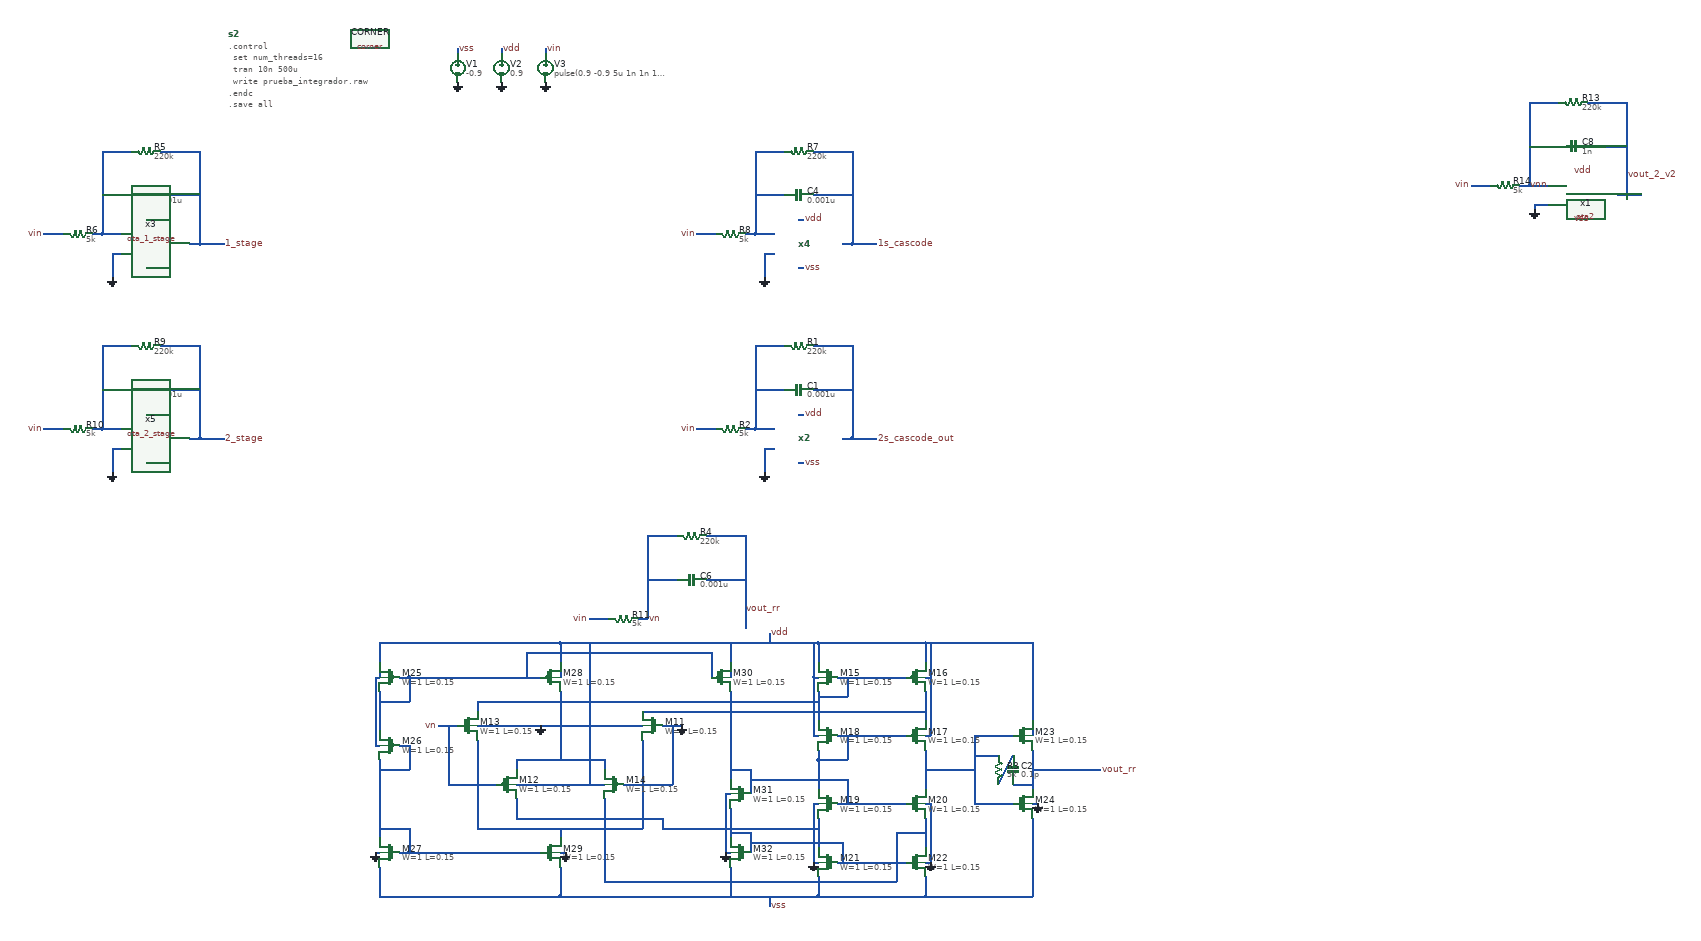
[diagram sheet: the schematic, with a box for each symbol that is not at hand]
v {xschem version=3.4.5 file_version=1.2
}
G {}
K {}
V {}
S {}
E {}
B 2 400 -320 1200 80 {flags=graph
y1=-1
y2=1.2
ypos1=0
ypos2=2
divy=5
subdivy=1
unity=1
x1=0.00019323799
x2=0.00039803799
divx=5
subdivx=1
xlabmag=1.0
ylabmag=1.0
node="vin
1_stage"
color="4 5"
dataset=-1
unitx=1
logx=0
logy=0
}
B 2 400 80 1200 480 {flags=graph
y1=-1
y2=1.3
ypos1=0
ypos2=2
divy=5
subdivy=1
unity=1
x1=0.00019323799
x2=0.00039803799
divx=5
subdivx=1
xlabmag=1.0
ylabmag=1.0
node="vin
2_stage"
color="4 5"
dataset=-1
unitx=1
logx=0
logy=0
}
B 2 1740 -320 2540 80 {flags=graph
y1=-1
y2=1
ypos1=0
ypos2=2
divy=5
subdivy=1
unity=1
x1=0.00019323799
x2=0.00039803799
divx=5
subdivx=1
xlabmag=1.0
ylabmag=1.0
node="vin
1s_cascode"
color="4 5"
dataset=-1
unitx=1
logx=0
logy=0
}
B 2 1740 80 2540 480 {flags=graph
y1=-0.9
y2=0.9
ypos1=0
ypos2=2
divy=5
subdivy=1
unity=1
x1=0.00019323799
x2=0.00039803799
divx=5
subdivx=1
xlabmag=1.0
ylabmag=1.0
node="vin
2s_cascode_out"
color="4 5"
dataset=-1
unitx=1
logx=0
logy=0
}
B 2 2100 540 2900 940 {flags=graph
y1=-1.1
y2=1.1
ypos1=0
ypos2=2
divy=5
subdivy=1
unity=1
x1=0.00019323799
x2=0.00039803799
divx=5
subdivx=1
xlabmag=1.0
ylabmag=1.0
node="vin
vout_rr"
color="4 5"
dataset=-1
unitx=1
logx=0
logy=0
}
B 2 1740 80 2540 480 {flags=graph
y1=-0.9
y2=0.9
ypos1=0
ypos2=2
divy=5
subdivy=1
unity=1
x1=0.00019323799
x2=0.00039803799
divx=5
subdivx=1
xlabmag=1.0
ylabmag=1.0
node="vin
2s_cascode_out"
color="4 5"
dataset=-1
unitx=1
logx=0
logy=0
}
B 2 1740 80 2540 480 {flags=graph
y1=-0.9
y2=0.9
ypos1=0
ypos2=2
divy=5
subdivy=1
unity=1
x1=0.00019323799
x2=0.00039803799
divx=5
subdivx=1
xlabmag=1.0
ylabmag=1.0
node="vin
2s_cascode_out"
color="4 5"
dataset=-1
unitx=1
logx=0
logy=0
}
B 2 3550 -190 4350 210 {flags=graph
y1=-0.9
y2=0.9
ypos1=0
ypos2=2
divy=5
subdivy=1
unity=1
x1=0.00019323799
x2=0.00039803799
divx=5
subdivx=1
xlabmag=1.0
ylabmag=1.0
node="vin
vout_2_v2"
color="4 5"
dataset=-1
unitx=1
logx=0
logy=0
}
N 860 -460 860 -450 {
lab=vdd}
N 770 -460 770 -450 {
lab=vss}
N 950 -460 950 -450 {
lab=vin}
N 130 -110 140 -110 {
lab=vdd}
N 130 -10 140 -10 {
lab=vss}
N 40 -190 40 -80 {
lab=#net1}
N 240 -190 240 -60 {
lab=1_stage}
N 220 -60 240 -60 {
lab=1_stage}
N 40 -250 40 -190 {
lab=#net1}
N 40 -250 100 -250 {
lab=#net1}
N 160 -250 240 -250 {
lab=1_stage}
N 240 -250 240 -190 {
lab=1_stage}
N 40 -160 100 -160 {
lab=#net1}
N 160 -160 240 -160 {
lab=1_stage}
N 20 -80 40 -80 {
lab=#net1}
N -80 -80 -40 -80 {
lab=vin}
N 240 -60 290 -60 {
lab=1_stage}
N 60 -80 80 -80 {
lab=#net1}
N 60 -40 60 10 {
lab=GND}
N 60 -40 80 -40 {
lab=GND}
N 40 -80 60 -80 {
lab=#net1}
N 130 290 140 290 {
lab=vdd}
N 130 390 140 390 {
lab=vss}
N 40 210 40 320 {
lab=#net2}
N 240 210 240 340 {
lab=2_stage}
N 220 340 240 340 {
lab=2_stage}
N 40 150 40 210 {
lab=#net2}
N 40 150 100 150 {
lab=#net2}
N 160 150 240 150 {
lab=2_stage}
N 240 150 240 210 {
lab=2_stage}
N 40 240 100 240 {
lab=#net2}
N 160 240 240 240 {
lab=2_stage}
N 20 320 40 320 {
lab=#net2}
N -80 320 -40 320 {
lab=vin}
N 240 340 290 340 {
lab=2_stage}
N 60 320 80 320 {
lab=#net2}
N 60 360 60 410 {
lab=GND}
N 60 360 80 360 {
lab=GND}
N 40 320 60 320 {
lab=#net2}
N 1470 -110 1480 -110 {
lab=vdd}
N 1470 -10 1480 -10 {
lab=vss}
N 1380 -190 1380 -80 {
lab=#net3}
N 1580 -190 1580 -60 {
lab=1s_cascode}
N 1560 -60 1580 -60 {
lab=1s_cascode}
N 1380 -250 1380 -190 {
lab=#net3}
N 1380 -250 1440 -250 {
lab=#net3}
N 1500 -250 1580 -250 {
lab=1s_cascode}
N 1580 -250 1580 -190 {
lab=1s_cascode}
N 1380 -160 1440 -160 {
lab=#net3}
N 1500 -160 1580 -160 {
lab=1s_cascode}
N 1360 -80 1380 -80 {
lab=#net3}
N 1260 -80 1300 -80 {
lab=vin}
N 1580 -60 1630 -60 {
lab=1s_cascode}
N 1400 -80 1420 -80 {
lab=#net3}
N 1400 -40 1400 10 {
lab=GND}
N 1400 -40 1420 -40 {
lab=GND}
N 1380 -80 1400 -80 {
lab=#net3}
N 1470 290 1480 290 {
lab=vdd}
N 1470 390 1480 390 {
lab=vss}
N 1380 210 1380 320 {
lab=#net4}
N 1580 210 1580 340 {
lab=2s_cascode_out}
N 1560 340 1580 340 {
lab=2s_cascode_out}
N 1380 150 1380 210 {
lab=#net4}
N 1380 150 1440 150 {
lab=#net4}
N 1500 150 1580 150 {
lab=2s_cascode_out}
N 1580 150 1580 210 {
lab=2s_cascode_out}
N 1380 240 1440 240 {
lab=#net4}
N 1500 240 1580 240 {
lab=2s_cascode_out}
N 1360 320 1380 320 {
lab=#net4}
N 1260 320 1300 320 {
lab=vin}
N 1580 340 1630 340 {
lab=2s_cascode_out}
N 1400 320 1420 320 {
lab=#net4}
N 1400 360 1400 410 {
lab=GND}
N 1400 360 1420 360 {
lab=GND}
N 1380 320 1400 320 {
lab=#net4}
N 890 1000 890 1020 {
lab=#net5}
N 890 1000 1070 1000 {
lab=#net5}
N 1070 1000 1070 1020 {
lab=#net5}
N 810 960 810 1140 {
lab=#net6}
N 1150 960 1150 1140 {
lab=#net6}
N 810 1140 1150 1140 {
lab=#net6}
N 730 930 770 930 {
lab=vn}
N 750 930 750 1050 {
lab=vn}
N 750 1050 850 1050 {
lab=vn}
N 1110 1050 1210 1050 {
lab=GND}
N 1210 930 1210 1050 {
lab=GND}
N 1190 930 1230 930 {
lab=GND}
N 980 860 980 1000 {
lab=#net5}
N 980 760 980 800 {
lab=vdd}
N 980 1140 980 1160 {
lab=#net6}
N 1510 860 1510 920 {
lab=#net7}
N 1730 860 1730 920 {
lab=#net8}
N 1550 830 1690 830 {
lab=#net7}
N 1510 760 1510 800 {
lab=vdd}
N 1510 760 1730 760 {
lab=vdd}
N 1730 760 1730 800 {
lab=vdd}
N 1510 1000 1550 1000 {
lab=#net9}
N 1510 980 1510 1000 {
lab=#net9}
N 1510 1120 1510 1180 {
lab=#net10}
N 1730 1120 1730 1180 {
lab=#net11}
N 1510 1000 1510 1060 {
lab=#net9}
N 1730 980 1730 1060 {
lab=#net12}
N 1510 1240 1510 1280 {
lab=vss}
N 1510 1280 1730 1280 {
lab=vss}
N 1730 1240 1730 1280 {
lab=vss}
N 1550 1090 1690 1090 {
lab=#net13}
N 1550 1210 1690 1210 {
lab=#net14}
N 1310 1280 1510 1280 {
lab=vss}
N 980 1220 980 1280 {
lab=vss}
N 980 1280 1310 1280 {
lab=vss}
N 1150 900 1730 900 {
lab=#net8}
N 810 880 810 900 {
lab=#net7}
N 810 880 1490 880 {
lab=#net7}
N 1490 880 1510 880 {
lab=#net7}
N 1510 870 1570 870 {
lab=#net7}
N 1570 830 1570 870 {
lab=#net7}
N 890 1080 890 1120 {
lab=#net10}
N 890 1120 1190 1120 {
lab=#net10}
N 1190 1140 1510 1140 {
lab=#net10}
N 1070 1080 1070 1250 {
lab=#net11}
N 1070 1250 1670 1250 {
lab=#net11}
N 1670 1160 1670 1250 {
lab=#net11}
N 980 760 1510 760 {
lab=vdd}
N 1410 740 1410 760 {
lab=vdd}
N 1410 1280 1410 1300 {
lab=vss}
N 1550 950 1690 950 {
lab=#net9}
N 1570 950 1570 1000 {
lab=#net9}
N 1550 1000 1570 1000 {
lab=#net9}
N 1830 950 1830 1090 {
lab=#net12}
N 1730 760 1950 760 {
lab=vdd}
N 1950 760 1950 920 {
lab=vdd}
N 1730 1280 1950 1280 {
lab=vss}
N 1950 1120 1950 1280 {
lab=vss}
N 1950 980 1950 1060 {
lab=vout_rr}
N 1950 1020 2090 1020 {
lab=vout_rr}
N 810 930 1150 930 {
lab=GND}
N 890 1050 1070 1050 {
lab=vdd}
N 1040 760 1040 1050 {
lab=vdd}
N 1500 830 1510 830 {
lab=vdd}
N 1500 760 1500 830 {
lab=vdd}
N 1500 830 1500 950 {
lab=vdd}
N 1500 950 1510 950 {
lab=vdd}
N 1730 950 1740 950 {
lab=vdd}
N 1740 760 1740 950 {
lab=vdd}
N 1730 830 1740 830 {
lab=vdd}
N 1500 1090 1510 1090 {
lab=GND}
N 1500 1210 1510 1210 {
lab=GND}
N 1730 1090 1740 1090 {
lab=GND}
N 1730 1210 1740 1210 {
lab=GND}
N 1560 1170 1560 1210 {
lab=#net14}
N 1670 1150 1730 1150 {
lab=#net11}
N 1670 1150 1670 1160 {
lab=#net11}
N 1950 920 1950 950 {
lab=vdd}
N 650 830 670 830 {
lab=#net15}
N 670 830 670 880 {
lab=#net15}
N 610 880 670 880 {
lab=#net15}
N 610 860 610 940 {
lab=#net15}
N 610 1000 610 1160 {
lab=#net16}
N 610 1020 670 1020 {
lab=#net16}
N 670 970 670 1020 {
lab=#net16}
N 650 970 670 970 {
lab=#net16}
N 610 1220 610 1280 {
lab=vss}
N 610 1140 670 1140 {
lab=#net16}
N 670 1140 670 1190 {
lab=#net16}
N 650 1190 670 1190 {
lab=#net16}
N 600 970 610 970 {
lab=vdd}
N 600 830 600 970 {
lab=vdd}
N 600 830 610 830 {
lab=vdd}
N 610 800 610 830 {
lab=vdd}
N 610 760 610 800 {
lab=vdd}
N 980 800 980 830 {
lab=vdd}
N 910 780 910 830 {
lab=#net15}
N 910 780 1290 780 {
lab=#net15}
N 1290 780 1290 830 {
lab=#net15}
N 1330 760 1330 800 {
lab=vdd}
N 1330 800 1330 830 {
lab=vdd}
N 1190 1120 1190 1140 {
lab=#net10}
N 1330 860 1330 1040 {
lab=#net13}
N 1330 1100 1330 1160 {
lab=#net14}
N 1330 1220 1330 1280 {
lab=vss}
N 1330 1150 1370 1150 {
lab=#net14}
N 1370 1150 1370 1190 {
lab=#net14}
N 1370 1170 1560 1170 {
lab=#net14}
N 1330 1020 1370 1020 {
lab=#net13}
N 1370 1020 1370 1070 {
lab=#net13}
N 1570 1040 1570 1090 {
lab=#net13}
N 1390 1040 1570 1040 {
lab=#net13}
N 1370 1040 1390 1040 {
lab=#net13}
N 1320 1070 1330 1070 {
lab=GND}
N 1320 1070 1320 1190 {
lab=GND}
N 1320 1190 1330 1190 {
lab=GND}
N 610 760 980 760 {
lab=vdd}
N 670 830 940 830 {
lab=#net15}
N 610 1280 980 1280 {
lab=vss}
N 670 1190 940 1190 {
lab=#net16}
N 1730 1020 1830 1020 {
lab=#net12}
N 1830 950 1910 950 {
lab=#net12}
N 1830 1090 1910 1090 {
lab=#net12}
N 1830 990 1880 990 {
lab=#net12}
N 1880 1050 1910 990 {
lab=#net17}
N 1910 1050 1950 1050 {
lab=vout_rr}
N 1160 600 1160 710 {
lab=vn}
N 1360 600 1360 730 {
lab=vout_rr}
N 1160 540 1160 600 {
lab=vn}
N 1160 540 1220 540 {
lab=vn}
N 1280 540 1360 540 {
lab=vout_rr}
N 1360 540 1360 600 {
lab=vout_rr}
N 1160 630 1220 630 {
lab=vn}
N 1280 630 1360 630 {
lab=vout_rr}
N 1040 710 1080 710 {
lab=vin}
N 1140 710 1160 710 {
lab=vn}
N 2970 -290 2970 -180 {
lab=vnn}
N 3170 -290 3170 -160 {
lab=vout_2_v2}
N 2970 -350 2970 -290 {
lab=vnn}
N 2970 -350 3030 -350 {
lab=vnn}
N 3090 -350 3170 -350 {
lab=vout_2_v2}
N 3170 -350 3170 -290 {
lab=vout_2_v2}
N 2970 -260 3030 -260 {
lab=vnn}
N 3090 -260 3170 -260 {
lab=vout_2_v2}
N 2850 -180 2890 -180 {
lab=vin}
N 2950 -180 2970 -180 {
lab=vnn}
N 600 1190 610 1190 {
lab=GND}
N 980 1190 990 1190 {
lab=GND}
N 1500 1090 1500 1210 {
lab=GND}
N 1740 1090 1740 1210 {
lab=GND}
N 1950 1090 1960 1090 {
lab=GND}
N 3150 -160 3200 -160 {
lab=vout_2_v2}
N 2970 -180 3010 -180 {
lab=vnn}
N 2980 -140 3010 -140 {
lab=GND}
N 2980 -140 2980 -130 {
lab=GND}
C {devices/vsource.sym} 770 -420 0 0 {name=V1 value=-0.9}
C {devices/gnd.sym} 770 -390 0 0 {name=l1 lab=GND}
C {devices/vsource.sym} 860 -420 0 0 {name=V2 value=0.9}
C {devices/gnd.sym} 860 -390 0 0 {name=l2 lab=GND}
C {devices/lab_wire.sym} 860 -460 0 1 {name=p1 sig_type=std_logic lab=vdd}
C {devices/lab_wire.sym} 770 -460 0 1 {name=p2 sig_type=std_logic lab=vss}
C {devices/vsource.sym} 950 -420 0 0 {name=V3 value="pulse(0.9 -0.9 5u 1n 1n 10u 20u)"}
C {devices/gnd.sym} 950 -390 0 0 {name=l3 lab=GND}
C {devices/lab_wire.sym} 950 -460 0 1 {name=p5 sig_type=std_logic lab=vin}
C {sky130_fd_pr/corner.sym} 590 -480 0 0 {name=CORNER only_toplevel=true corner=tt}
C {devices/launcher.sym} 1280 -430 0 0 {name=h5
descr="load waves" 
tclcommand="xschem raw_read $netlist_dir/prueba_integrador.raw tran"
}
C {devices/lab_wire.sym} 140 -110 0 1 {name=p12 sig_type=std_logic lab=vdd}
C {devices/lab_wire.sym} 140 -10 2 0 {name=p13 sig_type=std_logic lab=vss}
C {devices/res.sym} 130 -250 1 0 {name=R5
value=220k
footprint=1206
device=resistor
m=1}
C {devices/res.sym} -10 -80 1 0 {name=R6
value=5k
footprint=1206
device=resistor
m=1}
C {devices/capa.sym} 130 -160 3 0 {name=C3
m=1
value=0.001u
footprint=1206
device="ceramic capacitor"}
C {devices/lab_wire.sym} -80 -80 0 0 {name=p14 sig_type=std_logic lab=vin}
C {devices/gnd.sym} 60 10 0 0 {name=l6 lab=GND}
C {devices/lab_wire.sym} 290 -60 0 1 {name=p15 sig_type=std_logic lab=1_stage}
C {/home/user/Documentos/ota_1_stage.sym} 130 -60 0 0 {name=x3}
C {devices/lab_wire.sym} 140 290 0 1 {name=p17 sig_type=std_logic lab=vdd}
C {devices/lab_wire.sym} 140 390 2 0 {name=p20 sig_type=std_logic lab=vss}
C {devices/res.sym} 130 150 1 0 {name=R9
value=220k
footprint=1206
device=resistor
m=1}
C {devices/res.sym} -10 320 1 0 {name=R10
value=5k
footprint=1206
device=resistor
m=1}
C {devices/capa.sym} 130 240 3 0 {name=C5
m=1
value=0.001u
footprint=1206
device="ceramic capacitor"}
C {devices/lab_wire.sym} -80 320 0 0 {name=p21 sig_type=std_logic lab=vin}
C {devices/gnd.sym} 60 410 0 0 {name=l8 lab=GND}
C {devices/lab_wire.sym} 290 340 0 1 {name=p22 sig_type=std_logic lab=2_stage}
C {/home/user/Documentos/ota_2_stage.sym} 130 340 0 0 {name=x5}
C {devices/lab_wire.sym} 1480 -110 0 1 {name=p16 sig_type=std_logic lab=vdd}
C {devices/lab_wire.sym} 1480 -10 2 0 {name=p18 sig_type=std_logic lab=vss}
C {devices/res.sym} 1470 -250 1 0 {name=R7
value=220k
footprint=1206
device=resistor
m=1}
C {devices/res.sym} 1330 -80 1 0 {name=R8
value=5k
footprint=1206
device=resistor
m=1}
C {devices/capa.sym} 1470 -160 3 0 {name=C4
m=1
value=0.001u
footprint=1206
device="ceramic capacitor"}
C {devices/lab_wire.sym} 1260 -80 0 0 {name=p19 sig_type=std_logic lab=vin}
C {devices/gnd.sym} 1400 10 0 0 {name=l7 lab=GND}
C {devices/lab_wire.sym} 1630 -60 0 1 {name=p23 sig_type=std_logic lab=1s_cascode}
C {/home/user/Documentos/ota_1_stage_cascode.sym} 1470 -60 0 0 {name=x4}
C {devices/lab_wire.sym} 1480 290 0 1 {name=p3 sig_type=std_logic lab=vdd}
C {devices/lab_wire.sym} 1480 390 2 0 {name=p4 sig_type=std_logic lab=vss}
C {devices/res.sym} 1470 150 1 0 {name=R1
value=220k
footprint=1206
device=resistor
m=1}
C {devices/res.sym} 1330 320 1 0 {name=R2
value=5k
footprint=1206
device=resistor
m=1}
C {devices/capa.sym} 1470 240 3 0 {name=C1
m=1
value=0.001u
footprint=1206
device="ceramic capacitor"}
C {devices/lab_wire.sym} 1260 320 0 0 {name=p6 sig_type=std_logic lab=vin}
C {devices/gnd.sym} 1400 410 0 0 {name=l4 lab=GND}
C {devices/lab_wire.sym} 1630 340 0 1 {name=p7 sig_type=std_logic lab=2s_cascode_out}
C {devices/code_shown.sym} 300 -490 0 0 {name=s2 only_toplevel=false value="
.control
 set num_threads=16
 tran 10n 500u
 write prueba_integrador.raw
.endc
.save all" }
C {/home/user/Documentos/ota_2_stage_cascode_out.sym} 1470 340 0 0 {name=x2}
C {sky130_fd_pr/pfet_01v8.sym} 870 1050 0 0 {name=M12
L=0.15
W=1
nf=1 mult=1
model=pfet_01v8
spiceprefix=X
}
C {sky130_fd_pr/nfet_01v8.sym} 790 930 0 0 {name=M13
L=0.15
W=1  
nf=1 mult=1
model=nfet_01v8
spiceprefix=X
}
C {sky130_fd_pr/nfet_01v8.sym} 1170 930 0 1 {name=M11
L=0.15
W=1  
nf=1 mult=1
model=nfet_01v8
spiceprefix=X
}
C {sky130_fd_pr/pfet_01v8.sym} 1090 1050 0 1 {name=M14
L=0.15
W=1
nf=1 mult=1
model=pfet_01v8
spiceprefix=X
}
C {sky130_fd_pr/pfet_01v8.sym} 1530 830 0 1 {name=M15
L=0.15
W=1
nf=1 mult=1
model=pfet_01v8
spiceprefix=X
}
C {sky130_fd_pr/pfet_01v8.sym} 1710 830 0 0 {name=M16
L=0.15
W=1
nf=1 mult=1
model=pfet_01v8
spiceprefix=X
}
C {sky130_fd_pr/pfet_01v8.sym} 1710 950 0 0 {name=M17
L=0.15
W=1
nf=1 mult=1
model=pfet_01v8
spiceprefix=X
}
C {sky130_fd_pr/pfet_01v8.sym} 1530 950 0 1 {name=M18
L=0.15
W=1
nf=1 mult=1
model=pfet_01v8
spiceprefix=X
}
C {sky130_fd_pr/nfet_01v8.sym} 1530 1090 0 1 {name=M19
L=0.15
W=1  
nf=1 mult=1
model=nfet_01v8
spiceprefix=X
}
C {sky130_fd_pr/nfet_01v8.sym} 1710 1090 0 0 {name=M20
L=0.15
W=1  
nf=1 mult=1
model=nfet_01v8
spiceprefix=X
}
C {sky130_fd_pr/nfet_01v8.sym} 1530 1210 0 1 {name=M21
L=0.15
W=1  
nf=1 mult=1
model=nfet_01v8
spiceprefix=X
}
C {sky130_fd_pr/nfet_01v8.sym} 1710 1210 0 0 {name=M22
L=0.15
W=1  
nf=1 mult=1
model=nfet_01v8
spiceprefix=X
}
C {devices/lab_wire.sym} 730 930 0 0 {name=p9 sig_type=std_logic lab=vn}
C {devices/lab_wire.sym} 1410 740 0 1 {name=p10 sig_type=std_logic lab=vdd}
C {sky130_fd_pr/pfet_01v8.sym} 1930 950 0 0 {name=M23
L=0.15
W=1
nf=1 mult=1
model=pfet_01v8
spiceprefix=X
}
C {sky130_fd_pr/nfet_01v8.sym} 1930 1090 0 0 {name=M24
L=0.15
W=1  
nf=1 mult=1
model=nfet_01v8
spiceprefix=X
}
C {devices/lab_wire.sym} 2090 1020 0 1 {name=p11 sig_type=std_logic lab=vout_rr}
C {sky130_fd_pr/pfet_01v8.sym} 630 830 0 1 {name=M25
L=0.15
W=1
nf=1 mult=1
model=pfet_01v8
spiceprefix=X
}
C {sky130_fd_pr/pfet_01v8.sym} 630 970 0 1 {name=M26
L=0.15
W=1
nf=1 mult=1
model=pfet_01v8
spiceprefix=X
}
C {sky130_fd_pr/nfet_01v8.sym} 630 1190 0 1 {name=M27
L=0.15
W=1  
nf=1 mult=1
model=nfet_01v8
spiceprefix=X
}
C {sky130_fd_pr/pfet_01v8.sym} 960 830 0 0 {name=M28
L=0.15
W=1
nf=1 mult=1
model=pfet_01v8
spiceprefix=X
}
C {sky130_fd_pr/nfet_01v8.sym} 960 1190 0 0 {name=M29
L=0.15
W=1  
nf=1 mult=1
model=nfet_01v8
spiceprefix=X
}
C {sky130_fd_pr/pfet_01v8.sym} 1310 830 0 0 {name=M30
L=0.15
W=1
nf=1 mult=1
model=pfet_01v8
spiceprefix=X
}
C {sky130_fd_pr/nfet_01v8.sym} 1350 1070 0 1 {name=M31
L=0.15
W=1  
nf=1 mult=1
model=nfet_01v8
spiceprefix=X
}
C {sky130_fd_pr/nfet_01v8.sym} 1350 1190 0 1 {name=M32
L=0.15
W=1  
nf=1 mult=1
model=nfet_01v8
spiceprefix=X
}
C {devices/capa.sym} 1910 1020 0 0 {name=C2
m=1
value=0.1p
footprint=1206
device="ceramic capacitor"}
C {devices/res.sym} 1880 1020 0 0 {name=R3
value=5k
footprint=1206
device=resistor
m=1}
C {devices/gnd.sym} 1230 930 0 0 {name=l5 lab=GND}
C {devices/res.sym} 1250 540 1 0 {name=R4
value=220k
footprint=1206
device=resistor
m=1}
C {devices/capa.sym} 1250 630 3 0 {name=C6
m=1
value=0.001u
footprint=1206
device="ceramic capacitor"}
C {devices/res.sym} 1110 710 1 0 {name=R11
value=5k
footprint=1206
device=resistor
m=1}
C {devices/lab_wire.sym} 1040 710 0 0 {name=p8 sig_type=std_logic lab=vin}
C {devices/lab_wire.sym} 1160 710 0 1 {name=p24 sig_type=std_logic lab=vn}
C {devices/lab_wire.sym} 1360 690 0 1 {name=p25 sig_type=std_logic lab=vout_rr}
C {devices/lab_wire.sym} 1410 1300 2 0 {name=p26 sig_type=std_logic lab=vss}
C {devices/res.sym} 3060 -350 1 0 {name=R13
value=220k
footprint=1206
device=resistor
m=1}
C {devices/capa.sym} 3060 -260 3 0 {name=C8
m=1
value=1n
footprint=1206
device="ceramic capacitor"}
C {devices/res.sym} 2920 -180 1 0 {name=R14
value=5k
footprint=1206
device=resistor
m=1}
C {devices/lab_wire.sym} 2850 -180 0 0 {name=p29 sig_type=std_logic lab=vin}
C {devices/lab_wire.sym} 2970 -180 0 1 {name=p30 sig_type=std_logic lab=vnn}
C {devices/lab_wire.sym} 3170 -200 0 1 {name=p31 sig_type=std_logic lab=vout_2_v2}
C {devices/gnd.sym} 600 1190 1 1 {name=l11 lab=GND}
C {devices/gnd.sym} 940 930 0 1 {name=l12 lab=GND}
C {devices/gnd.sym} 990 1190 3 0 {name=l13 lab=GND}
C {devices/gnd.sym} 1320 1190 0 1 {name=l14 lab=GND}
C {devices/gnd.sym} 1500 1210 0 1 {name=l16 lab=GND}
C {devices/gnd.sym} 1740 1210 0 0 {name=l17 lab=GND}
C {devices/gnd.sym} 1960 1090 3 0 {name=l19 lab=GND}
C {/home/user/Documentos/ota2.sym} 3060 -160 0 0 {name=x1}
C {devices/lab_wire.sym} 3060 -210 0 1 {name=p33 sig_type=std_logic lab=vdd}
C {devices/lab_wire.sym} 3060 -110 2 0 {name=p34 sig_type=std_logic lab=vss}
C {devices/gnd.sym} 2980 -130 0 0 {name=l20 lab=GND}
